VERSION 5.7 ;
BUSBITCHARS "[]" ;
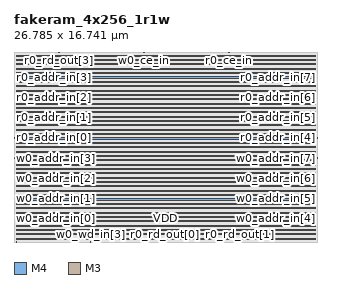
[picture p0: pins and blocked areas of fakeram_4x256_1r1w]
MACRO fakeram_4x256_1r1w
  FOREIGN fakeram_4x256_1r1w 0 0 ;
  SYMMETRY X Y R90 ;
  SIZE 26.785 BY 16.741 ;
  CLASS BLOCK ;
  PIN w0_wd_in[0]
    DIRECTION INPUT ;
    USE SIGNAL ;
    SHAPE ABUTMENT ;
    PORT
      LAYER M4 ;
      RECT 0.000 0.276 0.072 0.300 ;
    END
  END w0_wd_in[0]
  PIN w0_wd_in[1]
    DIRECTION INPUT ;
    USE SIGNAL ;
    SHAPE ABUTMENT ;
    PORT
      LAYER M4 ;
      RECT 26.713 0.276 26.785 0.300 ;
    END
  END w0_wd_in[1]
  PIN w0_wd_in[2]
    DIRECTION INPUT ;
    USE SIGNAL ;
    SHAPE ABUTMENT ;
    PORT
      LAYER M3 ;
      RECT 0.207 0.000 0.225 0.054 ;
    END
  END w0_wd_in[2]
  PIN w0_wd_in[3]
    DIRECTION INPUT ;
    USE SIGNAL ;
    SHAPE ABUTMENT ;
    PORT
      LAYER M3 ;
      RECT 6.759 0.000 6.777 0.054 ;
    END
  END w0_wd_in[3]
  PIN r0_rd_out[0]
    DIRECTION OUTPUT ;
    USE SIGNAL ;
    SHAPE ABUTMENT ;
    PORT
      LAYER M3 ;
      RECT 13.311 0.000 13.329 0.054 ;
    END
  END r0_rd_out[0]
  PIN r0_rd_out[1]
    DIRECTION OUTPUT ;
    USE SIGNAL ;
    SHAPE ABUTMENT ;
    PORT
      LAYER M3 ;
      RECT 19.863 0.000 19.881 0.054 ;
    END
  END r0_rd_out[1]
  PIN r0_rd_out[2]
    DIRECTION OUTPUT ;
    USE SIGNAL ;
    SHAPE ABUTMENT ;
    PORT
      LAYER M3 ;
      RECT 0.207 16.687 0.225 16.741 ;
    END
  END r0_rd_out[2]
  PIN r0_rd_out[3]
    DIRECTION OUTPUT ;
    USE SIGNAL ;
    SHAPE ABUTMENT ;
    PORT
      LAYER M3 ;
      RECT 3.951 16.687 3.969 16.741 ;
    END
  END r0_rd_out[3]
  PIN w0_addr_in[0]
    DIRECTION INPUT ;
    USE SIGNAL ;
    SHAPE ABUTMENT ;
    PORT
      LAYER M4 ;
      RECT 0.000 2.052 0.072 2.076 ;
    END
  END w0_addr_in[0]
  PIN w0_addr_in[1]
    DIRECTION INPUT ;
    USE SIGNAL ;
    SHAPE ABUTMENT ;
    PORT
      LAYER M4 ;
      RECT 0.000 3.828 0.072 3.852 ;
    END
  END w0_addr_in[1]
  PIN w0_addr_in[2]
    DIRECTION INPUT ;
    USE SIGNAL ;
    SHAPE ABUTMENT ;
    PORT
      LAYER M4 ;
      RECT 0.000 5.604 0.072 5.628 ;
    END
  END w0_addr_in[2]
  PIN w0_addr_in[3]
    DIRECTION INPUT ;
    USE SIGNAL ;
    SHAPE ABUTMENT ;
    PORT
      LAYER M4 ;
      RECT 0.000 7.380 0.072 7.404 ;
    END
  END w0_addr_in[3]
  PIN w0_addr_in[4]
    DIRECTION INPUT ;
    USE SIGNAL ;
    SHAPE ABUTMENT ;
    PORT
      LAYER M4 ;
      RECT 26.713 2.052 26.785 2.076 ;
    END
  END w0_addr_in[4]
  PIN w0_addr_in[5]
    DIRECTION INPUT ;
    USE SIGNAL ;
    SHAPE ABUTMENT ;
    PORT
      LAYER M4 ;
      RECT 26.713 3.828 26.785 3.852 ;
    END
  END w0_addr_in[5]
  PIN w0_addr_in[6]
    DIRECTION INPUT ;
    USE SIGNAL ;
    SHAPE ABUTMENT ;
    PORT
      LAYER M4 ;
      RECT 26.713 5.604 26.785 5.628 ;
    END
  END w0_addr_in[6]
  PIN w0_addr_in[7]
    DIRECTION INPUT ;
    USE SIGNAL ;
    SHAPE ABUTMENT ;
    PORT
      LAYER M4 ;
      RECT 26.713 7.380 26.785 7.404 ;
    END
  END w0_addr_in[7]
  PIN r0_addr_in[0]
    DIRECTION INPUT ;
    USE SIGNAL ;
    SHAPE ABUTMENT ;
    PORT
      LAYER M4 ;
      RECT 0.000 9.156 0.072 9.180 ;
    END
  END r0_addr_in[0]
  PIN r0_addr_in[1]
    DIRECTION INPUT ;
    USE SIGNAL ;
    SHAPE ABUTMENT ;
    PORT
      LAYER M4 ;
      RECT 0.000 10.932 0.072 10.956 ;
    END
  END r0_addr_in[1]
  PIN r0_addr_in[2]
    DIRECTION INPUT ;
    USE SIGNAL ;
    SHAPE ABUTMENT ;
    PORT
      LAYER M4 ;
      RECT 0.000 12.708 0.072 12.732 ;
    END
  END r0_addr_in[2]
  PIN r0_addr_in[3]
    DIRECTION INPUT ;
    USE SIGNAL ;
    SHAPE ABUTMENT ;
    PORT
      LAYER M4 ;
      RECT 0.000 14.484 0.072 14.508 ;
    END
  END r0_addr_in[3]
  PIN r0_addr_in[4]
    DIRECTION INPUT ;
    USE SIGNAL ;
    SHAPE ABUTMENT ;
    PORT
      LAYER M4 ;
      RECT 26.713 9.156 26.785 9.180 ;
    END
  END r0_addr_in[4]
  PIN r0_addr_in[5]
    DIRECTION INPUT ;
    USE SIGNAL ;
    SHAPE ABUTMENT ;
    PORT
      LAYER M4 ;
      RECT 26.713 10.932 26.785 10.956 ;
    END
  END r0_addr_in[5]
  PIN r0_addr_in[6]
    DIRECTION INPUT ;
    USE SIGNAL ;
    SHAPE ABUTMENT ;
    PORT
      LAYER M4 ;
      RECT 26.713 12.708 26.785 12.732 ;
    END
  END r0_addr_in[6]
  PIN r0_addr_in[7]
    DIRECTION INPUT ;
    USE SIGNAL ;
    SHAPE ABUTMENT ;
    PORT
      LAYER M4 ;
      RECT 26.713 14.484 26.785 14.508 ;
    END
  END r0_addr_in[7]
  PIN w0_we_in
    DIRECTION INPUT ;
    USE SIGNAL ;
    SHAPE ABUTMENT ;
    PORT
      LAYER M3 ;
      RECT 7.695 16.687 7.713 16.741 ;
    END
  END w0_we_in
  PIN w0_ce_in
    DIRECTION INPUT ;
    USE SIGNAL ;
    SHAPE ABUTMENT ;
    PORT
      LAYER M3 ;
      RECT 11.439 16.687 11.457 16.741 ;
    END
  END w0_ce_in
  PIN w0_clk
    DIRECTION INPUT ;
    USE SIGNAL ;
    SHAPE ABUTMENT ;
    PORT
      LAYER M3 ;
      RECT 15.183 16.687 15.201 16.741 ;
    END
  END w0_clk
  PIN r0_ce_in
    DIRECTION INPUT ;
    USE SIGNAL ;
    SHAPE ABUTMENT ;
    PORT
      LAYER M3 ;
      RECT 18.927 16.687 18.945 16.741 ;
    END
  END r0_ce_in
  PIN r0_clk
    DIRECTION INPUT ;
    USE SIGNAL ;
    SHAPE ABUTMENT ;
    PORT
      LAYER M3 ;
      RECT 22.671 16.687 22.689 16.741 ;
    END
  END r0_clk
  PIN VSS
    DIRECTION INOUT ;
    USE GROUND ;
    PORT
      LAYER M4 ;
      RECT 0.216 0.240 26.569 0.336 ;
      RECT 0.216 1.008 26.569 1.104 ;
      RECT 0.216 1.776 26.569 1.872 ;
      RECT 0.216 2.544 26.569 2.640 ;
      RECT 0.216 3.312 26.569 3.408 ;
      RECT 0.216 4.080 26.569 4.176 ;
      RECT 0.216 4.848 26.569 4.944 ;
      RECT 0.216 5.616 26.569 5.712 ;
      RECT 0.216 6.384 26.569 6.480 ;
      RECT 0.216 7.152 26.569 7.248 ;
      RECT 0.216 7.920 26.569 8.016 ;
      RECT 0.216 8.688 26.569 8.784 ;
      RECT 0.216 9.456 26.569 9.552 ;
      RECT 0.216 10.224 26.569 10.320 ;
      RECT 0.216 10.992 26.569 11.088 ;
      RECT 0.216 11.760 26.569 11.856 ;
      RECT 0.216 12.528 26.569 12.624 ;
      RECT 0.216 13.296 26.569 13.392 ;
      RECT 0.216 14.064 26.569 14.160 ;
      RECT 0.216 14.832 26.569 14.928 ;
      RECT 0.216 15.600 26.569 15.696 ;
      RECT 0.216 16.368 26.569 16.464 ;
    END
  END VSS
  PIN VDD
    DIRECTION INOUT ;
    USE POWER ;
    PORT
      LAYER M4 ;
      RECT 0.216 0.624 26.569 0.720 ;
      RECT 0.216 1.392 26.569 1.488 ;
      RECT 0.216 2.160 26.569 2.256 ;
      RECT 0.216 2.928 26.569 3.024 ;
      RECT 0.216 3.696 26.569 3.792 ;
      RECT 0.216 4.464 26.569 4.560 ;
      RECT 0.216 5.232 26.569 5.328 ;
      RECT 0.216 6.000 26.569 6.096 ;
      RECT 0.216 6.768 26.569 6.864 ;
      RECT 0.216 7.536 26.569 7.632 ;
      RECT 0.216 8.304 26.569 8.400 ;
      RECT 0.216 9.072 26.569 9.168 ;
      RECT 0.216 9.840 26.569 9.936 ;
      RECT 0.216 10.608 26.569 10.704 ;
      RECT 0.216 11.376 26.569 11.472 ;
      RECT 0.216 12.144 26.569 12.240 ;
      RECT 0.216 12.912 26.569 13.008 ;
      RECT 0.216 13.680 26.569 13.776 ;
      RECT 0.216 14.448 26.569 14.544 ;
      RECT 0.216 15.216 26.569 15.312 ;
      RECT 0.216 15.984 26.569 16.080 ;
    END
  END VDD
  OBS
    LAYER M1 ;
    RECT 0 0 26.785 16.741 ;
    LAYER M2 ;
    RECT 0 0 26.785 16.741 ;
    LAYER M3 ;
    RECT 0 0 26.785 16.741 ;
    LAYER M4 ;
    RECT 0 0 26.785 16.741 ;
  END
END fakeram_4x256_1r1w

END LIBRARY
